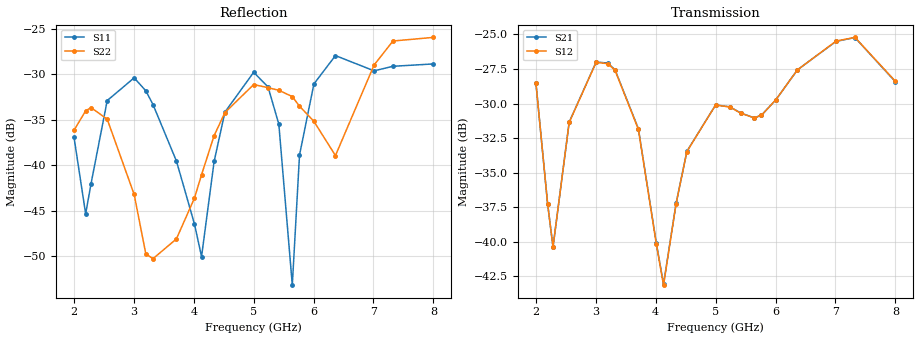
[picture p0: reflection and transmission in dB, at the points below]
!Agilent Technologies,E8364B,MY43040699,A.07.50.67
!Agilent E8364B: A.07.50.67
!Date: Friday, June 06, 2025 09:16:34
!Correction: S11(Full 2 Port(1,2))
!S21(Full 2 Port(1,2))
!S12(Full 2 Port(1,2))
!S22(Full 2 Port(1,2))
!S2P File: Measurements: S11, S21, S12, S22:
# Hz S  dB  R 50
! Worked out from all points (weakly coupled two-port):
!   401 points, 2 GHz to 8 GHz, reference 50 ohm
!   highest |S21| = -25.22 dB at 7.325 GHz (marker M1); lowest = -43.1 dB at 4.13 GHz (marker M2)
!   lowest |S11| = -53.2 dB at 5.645 GHz (marker M3), VSWR 1.00, Z = 49.8 - j0.0436 ohm
!   |S11| at or under -10 dB: start of sweep to end of sweep
!   |S22| runs from -50.3 to -25.1 dB; largest |S21 - S12| = 0.00034
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2e9  -36.90 -2.0  -28.52 27.0  -28.53 27.2  -36.17 6.1
2.195e9  -45.36 28.5  -37.25 25.3  -37.26 25.3  -34.03 -20.0
2.285e9  -42.05 65.6  -40.37 60.5  -40.38 60.6  -33.67 -30.9
2.555e9  -32.90 59.1  -31.34 82.6  -31.36 82.6  -34.95 -68.3
3.005e9  -30.40 5.5  -26.99 18.3  -27.02 18.2  -43.23 -137.0
3.2e9  -31.83 -14.8  -27.07 -13.4  -27.11 -13.3  -49.78 164.4
3.32e9  -33.35 -23.9  -27.55 -33.5  -27.59 -33.4  -50.29 111.1
3.71e9  -39.54 -37.9  -31.81 -103.6  -31.86 -103.4  -48.12 56.0
4.01e9  -46.44 -70.2  -40.10 177.7  -40.16 177.9  -43.65 69.5
4.13e9  -50.06 -139.8  -43.06 111.4  -43.13 111.7  -41.06 70.3
4.34e9  -39.59 132.3  -37.20 20.1  -37.23 20.4  -36.75 51.5
4.52e9  -34.17 100.6  -33.45 -19.8  -33.47 -19.2  -34.22 30.9
5e9  -29.79 29.1  -30.09 -97.4  -30.10 -97.0  -31.14 -33.8
5.24e9  -31.40 -6.7  -30.24 -127.8  -30.25 -127.4  -31.48 -71.3
5.42e9  -35.50 -36.3  -30.68 -145.9  -30.70 -145.6  -31.77 -100.2
5.645e9  -53.20 -168.4  -31.03 -162.7  -31.03 -162.4  -32.46 -136.3
5.765e9  -38.91 119.3  -30.84 -170.1  -30.84 -169.9  -33.52 -152.0
6.005e9  -31.08 79.6  -29.73 173.2  -29.72 173.5  -35.18 177.9
6.365e9  -27.95 38.5  -27.56 139.0  -27.56 139.1  -38.95 177.8
7.01e9  -29.63 5.9  -25.50 65.3  -25.48 65.4  -28.99 178.8
7.325e9  -29.13 2.3  -25.22 28.0  -25.21 28.2  -26.35 158.0
8e9  -28.87 -41.4  -28.42 -50.8  -28.38 -50.6  -25.95 108.4
